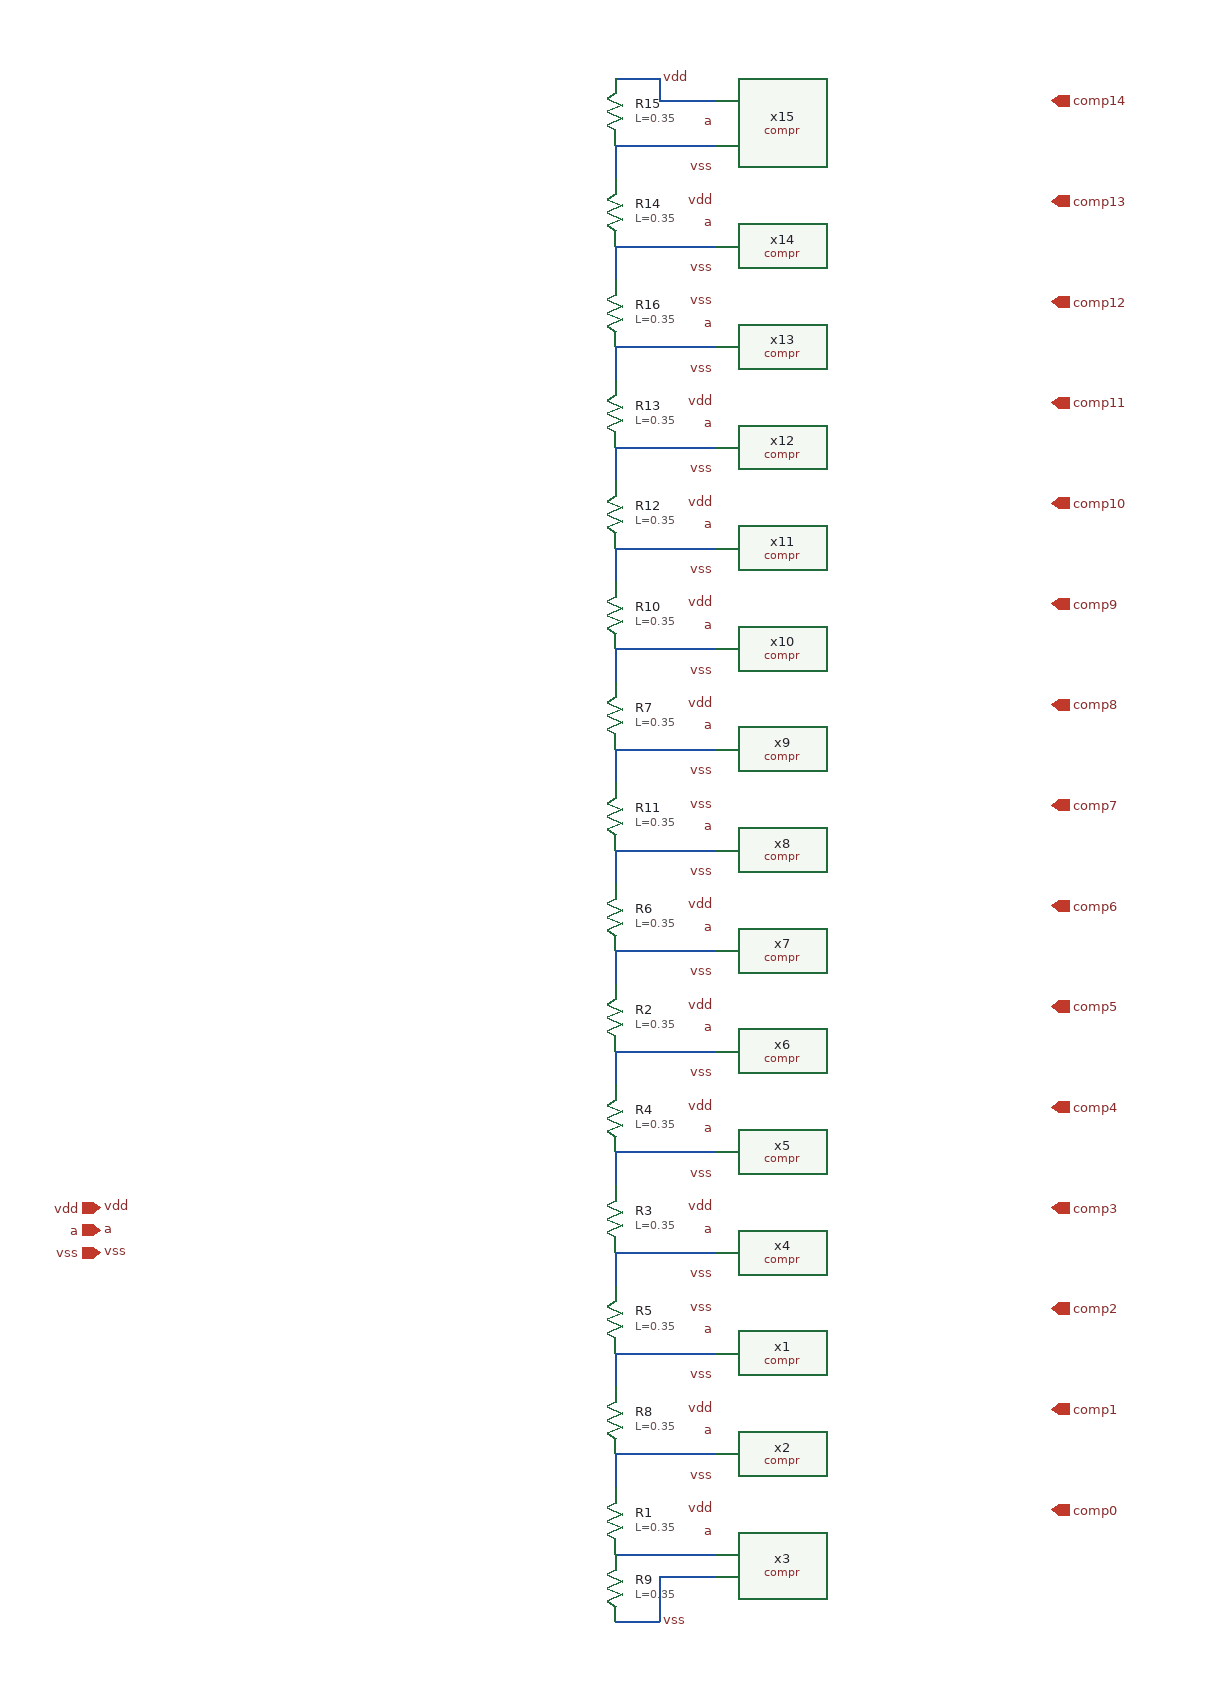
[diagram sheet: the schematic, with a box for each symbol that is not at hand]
v {xschem version=3.4.5 file_version=1.2
}
G {}
K {}
V {}
S {}
E {}
N 540 -380 540 -350 {
lab=#net1}
N 540 -380 630 -380 {
lab=#net1}
N 540 -290 630 -290 {
lab=#net2}
N 540 -650 540 -620 {
lab=#net3}
N 540 -650 630 -650 {
lab=#net3}
N 540 -560 630 -560 {
lab=#net4}
N 540 -560 540 -530 {
lab=#net4}
N 540 -470 540 -440 {
lab=#net5}
N 540 -470 630 -470 {
lab=#net5}
N 540 -230 580 -230 {
lab=vss}
N 580 -270 580 -230 {
lab=vss}
N 580 -270 630 -270 {
lab=vss}
N 540 -830 540 -800 {
lab=#net6}
N 540 -830 630 -830 {
lab=#net6}
N 540 -740 630 -740 {
lab=#net7}
N 540 -1100 540 -1070 {
lab=#net8}
N 540 -1100 630 -1100 {
lab=#net8}
N 540 -1010 630 -1010 {
lab=#net9}
N 540 -1010 540 -980 {
lab=#net9}
N 540 -920 540 -890 {
lab=#net10}
N 540 -920 630 -920 {
lab=#net10}
N 540 -1280 540 -1250 {
lab=#net11}
N 540 -1280 630 -1280 {
lab=#net11}
N 540 -1190 630 -1190 {
lab=#net12}
N 540 -1550 540 -1520 {
lab=#net13}
N 540 -1550 630 -1550 {
lab=#net13}
N 540 -1460 630 -1460 {
lab=#net14}
N 540 -1460 540 -1430 {
lab=#net14}
N 540 -1370 540 -1340 {
lab=#net15}
N 540 -1370 630 -1370 {
lab=#net15}
N 580 -1610 580 -1590 {
lab=vdd}
N 580 -1590 630 -1590 {
lab=vdd}
N 540 -1190 540 -1160 {
lab=#net12}
N 540 -740 540 -710 {
lab=#net7}
N 540 -1610 580 -1610 {
lab=vdd}
C {title.sym} 170 -40 0 0 {name=l3 author="Timonas Juonys"}
C {ipin.sym} 80 -580 0 0 {name=p7 lab=a
}
C {ipin.sym} 80 -600 0 0 {name=p14 lab=vdd}
C {lab_pin.sym} 80 -600 0 1 {name=p18 sig_type=std_logic lab=vdd}
C {lab_pin.sym} 80 -580 0 1 {name=p19 sig_type=std_logic lab=a}
C {ipin.sym} 80 -560 0 0 {name=p10 lab=vss
}
C {lab_pin.sym} 80 -560 0 1 {name=p79 sig_type=std_logic lab=vss}
C {opin.sym} 930 -600 0 0 {name=p61 lab=comp3}
C {opin.sym} 930 -690 0 0 {name=p21 lab=comp4}
C {opin.sym} 930 -780 0 0 {name=p56 lab=comp5}
C {opin.sym} 930 -870 0 0 {name=p57 lab=comp6}
C {opin.sym} 930 -960 0 0 {name=p58 lab=comp7}
C {opin.sym} 930 -1050 0 0 {name=p60 lab=comp8}
C {opin.sym} 930 -1140 0 0 {name=p62 lab=comp9}
C {opin.sym} 930 -1230 0 0 {name=p63 lab=comp10}
C {opin.sym} 930 -1320 0 0 {name=p64 lab=comp11}
C {/home/ttuser/Documents/aprx_adc/compr.sym} 780 -570 0 0 {name=x4}
C {/home/ttuser/Documents/aprx_adc/compr.sym} 780 -660 0 0 {name=x5}
C {/home/ttuser/Documents/aprx_adc/compr.sym} 780 -750 0 0 {name=x6}
C {/home/ttuser/Documents/aprx_adc/compr.sym} 780 -840 0 0 {name=x7}
C {/home/ttuser/Documents/aprx_adc/compr.sym} 780 -930 0 0 {name=x8}
C {/home/ttuser/Documents/aprx_adc/compr.sym} 780 -1020 0 0 {name=x9}
C {/home/ttuser/Documents/aprx_adc/compr.sym} 780 -1110 0 0 {name=x10}
C {/home/ttuser/Documents/aprx_adc/compr.sym} 780 -1200 0 0 {name=x11}
C {/home/ttuser/Documents/aprx_adc/compr.sym} 780 -1290 0 0 {name=x12}
C {/home/ttuser/Documents/aprx_adc/compr.sym} 780 -1380 0 0 {name=x13}
C {/home/ttuser/Documents/aprx_adc/compr.sym} 780 -1470 0 0 {name=x14}
C {/home/ttuser/Documents/aprx_adc/compr.sym} 780 -1560 0 0 {name=x15}
C {opin.sym} 930 -1410 0 0 {name=p2 lab=comp12}
C {opin.sym} 930 -1500 0 0 {name=p11 lab=comp13}
C {opin.sym} 930 -1590 0 0 {name=p13 lab=comp14}
C {opin.sym} 930 -510 0 0 {name=p5 lab=comp2}
C {/home/ttuser/Documents/aprx_adc/compr.sym} 780 -480 0 0 {name=x1}
C {lab_pin.sym} 630 -450 0 0 {name=p9 sig_type=std_logic lab=vss}
C {opin.sym} 930 -420 0 0 {name=p15 lab=comp1}
C {lab_pin.sym} 630 -400 0 0 {name=p16 sig_type=std_logic lab=a}
C {lab_pin.sym} 630 -420 0 0 {name=p17 sig_type=std_logic lab=vdd}
C {/home/ttuser/Documents/aprx_adc/compr.sym} 780 -390 0 0 {name=x2}
C {lab_pin.sym} 630 -360 0 0 {name=p20 sig_type=std_logic lab=vss}
C {opin.sym} 930 -330 0 0 {name=p23 lab=comp0}
C {lab_pin.sym} 630 -310 0 0 {name=p24 sig_type=std_logic lab=a}
C {lab_pin.sym} 630 -330 0 0 {name=p27 sig_type=std_logic lab=vdd}
C {/home/ttuser/Documents/aprx_adc/compr.sym} 780 -300 0 0 {name=x3}
C {/home/ttuser/pdk/sky130A/libs.tech/xschem/sky130_fd_pr/res_xhigh_po_0p35.sym} 540 -320 0 1 {name=R1
L=0.35
model=res_xhigh_po_0p35
spiceprefix=X
mult=1}
C {/home/ttuser/pdk/sky130A/libs.tech/xschem/sky130_fd_pr/res_xhigh_po_0p35.sym} 540 -410 0 1 {name=R8
L=0.35
model=res_xhigh_po_0p35
spiceprefix=X
mult=1}
C {lab_pin.sym} 630 -720 0 0 {name=p1 sig_type=std_logic lab=vss}
C {lab_pin.sym} 630 -670 0 0 {name=p4 sig_type=std_logic lab=a}
C {lab_pin.sym} 630 -690 0 0 {name=p6 sig_type=std_logic lab=vdd}
C {lab_pin.sym} 630 -630 0 0 {name=p8 sig_type=std_logic lab=vss}
C {lab_pin.sym} 630 -580 0 0 {name=p12 sig_type=std_logic lab=a}
C {lab_pin.sym} 630 -600 0 0 {name=p22 sig_type=std_logic lab=vdd}
C {/home/ttuser/pdk/sky130A/libs.tech/xschem/sky130_fd_pr/res_xhigh_po_0p35.sym} 540 -590 0 1 {name=R3
L=0.35
model=res_xhigh_po_0p35
spiceprefix=X
mult=1}
C {/home/ttuser/pdk/sky130A/libs.tech/xschem/sky130_fd_pr/res_xhigh_po_0p35.sym} 540 -680 0 1 {name=R4
L=0.35
model=res_xhigh_po_0p35
spiceprefix=X
mult=1}
C {/home/ttuser/pdk/sky130A/libs.tech/xschem/sky130_fd_pr/res_xhigh_po_0p35.sym} 540 -500 0 1 {name=R5
L=0.35
model=res_xhigh_po_0p35
spiceprefix=X
mult=1}
C {lab_pin.sym} 630 -540 0 0 {name=p25 sig_type=std_logic lab=vss}
C {lab_pin.sym} 630 -510 0 0 {name=p26 sig_type=std_logic lab=vss}
C {lab_pin.sym} 630 -490 0 0 {name=p28 sig_type=std_logic lab=a}
C {/home/ttuser/pdk/sky130A/libs.tech/xschem/sky130_fd_pr/res_xhigh_po_0p35.sym} 540 -260 0 1 {name=R9
L=0.35
model=res_xhigh_po_0p35
spiceprefix=X
mult=1}
C {lab_pin.sym} 580 -230 0 1 {name=p29 sig_type=std_logic lab=vss}
C {lab_pin.sym} 630 -900 0 0 {name=p3 sig_type=std_logic lab=vss}
C {lab_pin.sym} 630 -850 0 0 {name=p30 sig_type=std_logic lab=a}
C {lab_pin.sym} 630 -870 0 0 {name=p31 sig_type=std_logic lab=vdd}
C {lab_pin.sym} 630 -810 0 0 {name=p32 sig_type=std_logic lab=vss}
C {lab_pin.sym} 630 -760 0 0 {name=p33 sig_type=std_logic lab=a}
C {lab_pin.sym} 630 -780 0 0 {name=p34 sig_type=std_logic lab=vdd}
C {/home/ttuser/pdk/sky130A/libs.tech/xschem/sky130_fd_pr/res_xhigh_po_0p35.sym} 540 -770 0 1 {name=R2
L=0.35
model=res_xhigh_po_0p35
spiceprefix=X
mult=1}
C {/home/ttuser/pdk/sky130A/libs.tech/xschem/sky130_fd_pr/res_xhigh_po_0p35.sym} 540 -860 0 1 {name=R6
L=0.35
model=res_xhigh_po_0p35
spiceprefix=X
mult=1}
C {lab_pin.sym} 630 -1170 0 0 {name=p35 sig_type=std_logic lab=vss}
C {lab_pin.sym} 630 -1120 0 0 {name=p36 sig_type=std_logic lab=a}
C {lab_pin.sym} 630 -1140 0 0 {name=p37 sig_type=std_logic lab=vdd}
C {lab_pin.sym} 630 -1080 0 0 {name=p38 sig_type=std_logic lab=vss}
C {lab_pin.sym} 630 -1030 0 0 {name=p39 sig_type=std_logic lab=a}
C {lab_pin.sym} 630 -1050 0 0 {name=p40 sig_type=std_logic lab=vdd}
C {/home/ttuser/pdk/sky130A/libs.tech/xschem/sky130_fd_pr/res_xhigh_po_0p35.sym} 540 -1040 0 1 {name=R7
L=0.35
model=res_xhigh_po_0p35
spiceprefix=X
mult=1}
C {/home/ttuser/pdk/sky130A/libs.tech/xschem/sky130_fd_pr/res_xhigh_po_0p35.sym} 540 -1130 0 1 {name=R10
L=0.35
model=res_xhigh_po_0p35
spiceprefix=X
mult=1}
C {/home/ttuser/pdk/sky130A/libs.tech/xschem/sky130_fd_pr/res_xhigh_po_0p35.sym} 540 -950 0 1 {name=R11
L=0.35
model=res_xhigh_po_0p35
spiceprefix=X
mult=1}
C {lab_pin.sym} 630 -990 0 0 {name=p41 sig_type=std_logic lab=vss}
C {lab_pin.sym} 630 -960 0 0 {name=p42 sig_type=std_logic lab=vss}
C {lab_pin.sym} 630 -940 0 0 {name=p43 sig_type=std_logic lab=a}
C {lab_pin.sym} 630 -1350 0 0 {name=p44 sig_type=std_logic lab=vss}
C {lab_pin.sym} 630 -1300 0 0 {name=p45 sig_type=std_logic lab=a}
C {lab_pin.sym} 630 -1320 0 0 {name=p46 sig_type=std_logic lab=vdd}
C {lab_pin.sym} 630 -1260 0 0 {name=p47 sig_type=std_logic lab=vss}
C {lab_pin.sym} 630 -1210 0 0 {name=p48 sig_type=std_logic lab=a}
C {lab_pin.sym} 630 -1230 0 0 {name=p49 sig_type=std_logic lab=vdd}
C {/home/ttuser/pdk/sky130A/libs.tech/xschem/sky130_fd_pr/res_xhigh_po_0p35.sym} 540 -1220 0 1 {name=R12
L=0.35
model=res_xhigh_po_0p35
spiceprefix=X
mult=1}
C {/home/ttuser/pdk/sky130A/libs.tech/xschem/sky130_fd_pr/res_xhigh_po_0p35.sym} 540 -1310 0 1 {name=R13
L=0.35
model=res_xhigh_po_0p35
spiceprefix=X
mult=1}
C {lab_pin.sym} 630 -1570 0 0 {name=p51 sig_type=std_logic lab=a}
C {lab_pin.sym} 630 -1530 0 0 {name=p53 sig_type=std_logic lab=vss}
C {lab_pin.sym} 630 -1480 0 0 {name=p54 sig_type=std_logic lab=a}
C {lab_pin.sym} 630 -1500 0 0 {name=p55 sig_type=std_logic lab=vdd}
C {/home/ttuser/pdk/sky130A/libs.tech/xschem/sky130_fd_pr/res_xhigh_po_0p35.sym} 540 -1490 0 1 {name=R14
L=0.35
model=res_xhigh_po_0p35
spiceprefix=X
mult=1}
C {/home/ttuser/pdk/sky130A/libs.tech/xschem/sky130_fd_pr/res_xhigh_po_0p35.sym} 540 -1580 0 1 {name=R15
L=0.35
model=res_xhigh_po_0p35
spiceprefix=X
mult=1}
C {/home/ttuser/pdk/sky130A/libs.tech/xschem/sky130_fd_pr/res_xhigh_po_0p35.sym} 540 -1400 0 1 {name=R16
L=0.35
model=res_xhigh_po_0p35
spiceprefix=X
mult=1}
C {lab_pin.sym} 630 -1440 0 0 {name=p59 sig_type=std_logic lab=vss}
C {lab_pin.sym} 630 -1410 0 0 {name=p65 sig_type=std_logic lab=vss}
C {lab_pin.sym} 630 -1390 0 0 {name=p66 sig_type=std_logic lab=a}
C {lab_pin.sym} 580 -1610 0 1 {name=p50 sig_type=std_logic lab=vdd}
